VERSION 5.7 ;
  NOWIREEXTENSIONATPIN ON ;
  DIVIDERCHAR "/" ;
  BUSBITCHARS "[]" ;
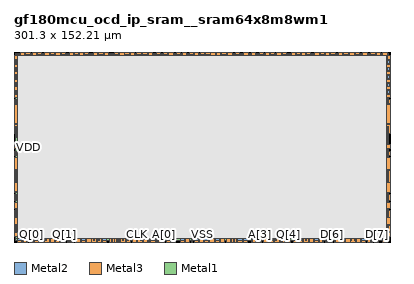
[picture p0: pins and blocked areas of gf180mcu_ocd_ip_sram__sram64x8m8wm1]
MACRO gf180mcu_ocd_ip_sram__sram64x8m8wm1
  CLASS BLOCK ;
  FOREIGN gf180mcu_ocd_ip_sram__sram64x8m8wm1 ;
  ORIGIN 0.000 0.000 ;
  SIZE 301.300 BY 152.210 ;
  PIN A[5]
    DIRECTION INPUT ;
    USE SIGNAL ;
    ANTENNADIFFAREA 0.928400 ;
    PORT
      LAYER Metal2 ;
        RECT 190.455 0.000 191.240 3.000 ;
    END
  END A[5]
  PIN A[4]
    DIRECTION INPUT ;
    USE SIGNAL ;
    ANTENNADIFFAREA 0.928400 ;
    PORT
      LAYER Metal2 ;
        RECT 193.070 0.000 193.855 3.000 ;
    END
  END A[4]
  PIN A[3]
    DIRECTION INPUT ;
    USE SIGNAL ;
    ANTENNADIFFAREA 0.928400 ;
    PORT
      LAYER Metal2 ;
        RECT 196.925 0.000 197.710 3.000 ;
    END
  END A[3]
  PIN A[2]
    DIRECTION INPUT ;
    USE SIGNAL ;
    ANTENNADIFFAREA 0.928400 ;
    PORT
      LAYER Metal2 ;
        RECT 108.005 0.000 108.790 3.000 ;
    END
  END A[2]
  PIN A[1]
    DIRECTION INPUT ;
    USE SIGNAL ;
    ANTENNADIFFAREA 0.928400 ;
    PORT
      LAYER Metal2 ;
        RECT 113.930 0.000 114.715 3.000 ;
    END
  END A[1]
  PIN A[0]
    DIRECTION INPUT ;
    USE SIGNAL ;
    ANTENNADIFFAREA 0.928400 ;
    PORT
      LAYER Metal2 ;
        RECT 119.850 0.000 120.630 3.000 ;
    END
  END A[0]
  PIN CEN
    DIRECTION INPUT ;
    USE SIGNAL ;
    ANTENNADIFFAREA 1.418650 ;
    PORT
      LAYER Metal2 ;
        RECT 176.195 0.000 176.980 3.000 ;
    END
  END CEN
  PIN CLK
    DIRECTION INPUT ;
    USE SIGNAL ;
    ANTENNAGATEAREA 9.738400 ;
    ANTENNADIFFAREA 0.490250 ;
    PORT
      LAYER Metal2 ;
        RECT 97.775 0.000 98.560 3.000 ;
    END
  END CLK
  PIN D[7]
    DIRECTION INPUT ;
    USE SIGNAL ;
    ANTENNAGATEAREA 0.249200 ;
    ANTENNADIFFAREA 0.490250 ;
    PORT
      LAYER Metal2 ;
        RECT 290.800 0.000 291.585 3.000 ;
    END
  END D[7]
  PIN D[6]
    DIRECTION INPUT ;
    USE SIGNAL ;
    ANTENNAGATEAREA 0.249200 ;
    ANTENNADIFFAREA 0.490250 ;
    PORT
      LAYER Metal2 ;
        RECT 254.605 0.000 255.385 3.000 ;
    END
  END D[6]
  PIN D[5]
    DIRECTION INPUT ;
    USE SIGNAL ;
    ANTENNAGATEAREA 0.249200 ;
    ANTENNADIFFAREA 0.490250 ;
    PORT
      LAYER Metal2 ;
        RECT 249.235 0.000 250.020 3.000 ;
    END
  END D[5]
  PIN D[4]
    DIRECTION INPUT ;
    USE SIGNAL ;
    ANTENNAGATEAREA 0.249200 ;
    ANTENNADIFFAREA 0.490250 ;
    PORT
      LAYER Metal2 ;
        RECT 214.060 0.000 214.845 3.000 ;
    END
  END D[4]
  PIN D[3]
    DIRECTION INPUT ;
    USE SIGNAL ;
    ANTENNAGATEAREA 0.249200 ;
    ANTENNADIFFAREA 0.490250 ;
    PORT
      LAYER Metal2 ;
        RECT 83.280 0.000 84.065 3.000 ;
    END
  END D[3]
  PIN D[2]
    DIRECTION INPUT ;
    USE SIGNAL ;
    ANTENNAGATEAREA 0.249200 ;
    ANTENNADIFFAREA 0.490250 ;
    PORT
      LAYER Metal2 ;
        RECT 47.085 0.000 47.870 3.000 ;
    END
  END D[2]
  PIN D[1]
    DIRECTION INPUT ;
    USE SIGNAL ;
    ANTENNAGATEAREA 0.249200 ;
    ANTENNADIFFAREA 0.490250 ;
    PORT
      LAYER Metal2 ;
        RECT 42.720 0.000 43.505 3.000 ;
    END
  END D[1]
  PIN D[0]
    DIRECTION INPUT ;
    USE SIGNAL ;
    ANTENNAGATEAREA 0.249200 ;
    ANTENNADIFFAREA 0.490250 ;
    PORT
      LAYER Metal2 ;
        RECT 6.520 0.000 7.305 3.000 ;
    END
  END D[0]
  PIN GWEN
    DIRECTION INPUT ;
    USE SIGNAL ;
    ANTENNAGATEAREA 3.141600 ;
    ANTENNADIFFAREA 0.490250 ;
    PORT
      LAYER Metal2 ;
        RECT 142.055 0.000 142.840 3.000 ;
    END
  END GWEN
  PIN Q[7]
    DIRECTION OUTPUT ;
    USE SIGNAL ;
    ANTENNADIFFAREA 5.315450 ;
    PORT
      LAYER Metal2 ;
        RECT 285.490 0.000 286.275 3.000 ;
    END
  END Q[7]
  PIN Q[6]
    DIRECTION OUTPUT ;
    USE SIGNAL ;
    ANTENNADIFFAREA 5.315450 ;
    PORT
      LAYER Metal2 ;
        RECT 256.960 0.000 257.740 3.000 ;
    END
  END Q[6]
  PIN Q[5]
    DIRECTION OUTPUT ;
    USE SIGNAL ;
    ANTENNADIFFAREA 5.315450 ;
    PORT
      LAYER Metal2 ;
        RECT 246.880 0.000 247.665 3.000 ;
    END
  END Q[5]
  PIN Q[4]
    DIRECTION OUTPUT ;
    USE SIGNAL ;
    ANTENNADIFFAREA 5.315450 ;
    PORT
      LAYER Metal2 ;
        RECT 219.350 0.000 220.135 3.000 ;
    END
  END Q[4]
  PIN Q[3]
    DIRECTION OUTPUT ;
    USE SIGNAL ;
    ANTENNADIFFAREA 5.315450 ;
    PORT
      LAYER Metal2 ;
        RECT 77.975 0.000 78.760 3.000 ;
    END
  END Q[3]
  PIN Q[2]
    DIRECTION OUTPUT ;
    USE SIGNAL ;
    ANTENNADIFFAREA 5.315450 ;
    PORT
      LAYER Metal2 ;
        RECT 49.440 0.000 50.225 3.000 ;
    END
  END Q[2]
  PIN Q[1]
    DIRECTION OUTPUT ;
    USE SIGNAL ;
    ANTENNADIFFAREA 5.315450 ;
    PORT
      LAYER Metal2 ;
        RECT 40.365 0.000 41.145 3.000 ;
    END
  END Q[1]
  PIN Q[0]
    DIRECTION OUTPUT ;
    USE SIGNAL ;
    ANTENNADIFFAREA 5.315450 ;
    PORT
      LAYER Metal2 ;
        RECT 13.830 0.000 14.610 3.000 ;
    END
  END Q[0]
  PIN VDD
    DIRECTION INOUT ;
    USE POWER ;
    PORT
      LAYER Metal2 ;
        RECT 2.470 149.260 298.830 149.410 ;
        RECT 2.465 149.210 298.830 149.260 ;
        RECT 2.465 3.000 3.000 149.210 ;
        RECT 298.300 145.630 298.830 149.210 ;
        RECT 298.300 4.330 298.835 145.630 ;
        RECT 298.300 3.000 298.830 4.330 ;
        RECT 2.465 1.410 5.970 3.000 ;
        RECT 2.470 0.985 5.970 1.410 ;
        RECT 295.330 0.985 298.830 3.000 ;
      LAYER Metal3 ;
        RECT 5.090 149.410 8.585 152.210 ;
        RECT 14.480 149.410 17.975 152.210 ;
        RECT 24.630 149.410 28.125 152.210 ;
        RECT 33.380 149.410 36.875 152.210 ;
        RECT 44.170 149.410 47.665 152.210 ;
        RECT 52.280 149.410 55.775 152.210 ;
        RECT 63.710 149.410 67.205 152.210 ;
        RECT 72.285 149.410 75.780 152.210 ;
        RECT 84.685 149.410 88.180 152.210 ;
        RECT 93.000 149.410 96.495 152.210 ;
        RECT 107.485 149.410 110.980 152.210 ;
        RECT 123.950 149.410 127.445 152.210 ;
        RECT 135.045 149.410 138.540 152.210 ;
        RECT 144.305 149.410 147.800 152.210 ;
        RECT 157.740 149.410 161.235 152.210 ;
        RECT 162.095 149.410 165.590 152.210 ;
        RECT 171.155 149.410 174.650 152.210 ;
        RECT 183.990 149.410 187.485 152.210 ;
        RECT 189.915 149.410 193.410 152.210 ;
        RECT 201.415 149.410 204.910 152.210 ;
        RECT 210.520 149.410 214.015 152.210 ;
        RECT 221.995 149.410 225.490 152.210 ;
        RECT 230.060 149.410 233.555 152.210 ;
        RECT 240.895 149.410 244.390 152.210 ;
        RECT 249.600 149.410 253.095 152.210 ;
        RECT 259.795 149.410 263.290 152.210 ;
        RECT 269.140 149.410 272.635 152.210 ;
        RECT 279.300 149.410 282.795 152.210 ;
        RECT 290.115 149.410 293.610 152.210 ;
        RECT 295.330 149.410 298.825 152.210 ;
        RECT 0.000 149.210 301.300 149.410 ;
        RECT 0.000 145.910 3.000 149.210 ;
        RECT 298.300 145.910 301.300 149.210 ;
        RECT 0.000 139.930 3.000 142.380 ;
        RECT 298.300 140.015 301.300 142.465 ;
        RECT 0.000 133.870 3.000 136.320 ;
        RECT 298.300 133.955 301.300 136.405 ;
        RECT 0.000 127.810 3.000 130.260 ;
        RECT 298.300 127.895 301.300 130.345 ;
        RECT 0.000 121.750 3.000 124.200 ;
        RECT 298.300 121.835 301.300 124.285 ;
        RECT 0.000 115.690 3.000 118.140 ;
        RECT 298.300 115.775 301.300 118.225 ;
        RECT 0.000 95.175 3.000 109.910 ;
        RECT 298.300 95.175 301.300 109.910 ;
        RECT 300.600 95.170 301.300 95.175 ;
        RECT 0.000 74.855 3.000 78.355 ;
        RECT 0.010 74.850 3.000 74.855 ;
        RECT 298.300 74.850 301.300 78.355 ;
        RECT 0.010 67.735 3.000 67.740 ;
        RECT 0.000 58.210 3.000 67.735 ;
        RECT 298.300 58.210 301.300 67.750 ;
        RECT 0.000 58.205 0.700 58.210 ;
        RECT 300.600 58.205 301.300 58.210 ;
        RECT 0.000 40.125 3.000 47.325 ;
        RECT 300.600 47.315 301.300 47.320 ;
        RECT 0.010 40.020 3.000 40.125 ;
        RECT 298.300 40.010 301.300 47.315 ;
        RECT 0.000 26.530 3.000 31.300 ;
        RECT 300.600 31.295 301.300 31.300 ;
        RECT 0.010 26.525 3.000 26.530 ;
        RECT 298.300 26.525 301.300 31.295 ;
        RECT 0.000 14.210 3.000 19.350 ;
        RECT 0.010 14.205 3.000 14.210 ;
        RECT 298.300 14.205 301.300 19.350 ;
        RECT 0.000 4.310 3.000 7.810 ;
        RECT 0.000 4.290 0.700 4.310 ;
        RECT 2.465 3.000 3.000 4.310 ;
        RECT 298.300 4.310 301.300 7.810 ;
        RECT 298.300 3.000 298.830 4.310 ;
        RECT 2.465 0.000 5.970 3.000 ;
        RECT 7.135 0.000 10.635 3.000 ;
        RECT 12.045 0.000 15.545 3.000 ;
        RECT 20.445 0.000 23.945 3.000 ;
        RECT 24.645 0.000 28.145 3.000 ;
        RECT 28.845 0.000 32.345 3.000 ;
        RECT 37.245 0.000 40.745 3.000 ;
        RECT 43.550 0.000 47.050 3.000 ;
        RECT 49.845 0.000 53.345 3.000 ;
        RECT 58.245 0.000 61.745 3.000 ;
        RECT 62.445 0.000 65.945 3.000 ;
        RECT 66.645 0.000 70.145 3.000 ;
        RECT 76.685 0.000 80.185 3.000 ;
        RECT 80.885 0.000 84.385 3.000 ;
        RECT 85.435 0.000 88.935 3.000 ;
        RECT 89.985 0.000 93.485 3.000 ;
        RECT 94.535 0.000 98.035 3.000 ;
        RECT 99.085 0.000 102.585 3.000 ;
        RECT 103.635 0.000 107.135 3.000 ;
        RECT 126.105 0.000 129.605 3.000 ;
        RECT 137.295 0.000 140.795 3.000 ;
        RECT 148.515 0.000 152.015 3.000 ;
        RECT 156.915 0.000 160.415 3.000 ;
        RECT 165.315 0.000 168.815 3.000 ;
        RECT 169.980 0.000 173.480 3.000 ;
        RECT 174.565 0.000 178.065 3.000 ;
        RECT 190.600 0.000 194.100 3.000 ;
        RECT 195.150 0.000 198.650 3.000 ;
        RECT 199.700 0.000 203.200 3.000 ;
        RECT 204.250 0.000 207.750 3.000 ;
        RECT 208.800 0.000 212.300 3.000 ;
        RECT 213.350 0.000 216.850 3.000 ;
        RECT 218.030 0.000 221.530 3.000 ;
        RECT 227.960 0.000 231.460 3.000 ;
        RECT 232.160 0.000 235.660 3.000 ;
        RECT 236.360 0.000 239.860 3.000 ;
        RECT 244.760 0.000 248.260 3.000 ;
        RECT 251.055 0.000 254.555 3.000 ;
        RECT 257.360 0.000 260.860 3.000 ;
        RECT 265.760 0.000 269.260 3.000 ;
        RECT 269.960 0.000 273.460 3.000 ;
        RECT 274.160 0.000 277.660 3.000 ;
        RECT 283.560 0.000 287.060 3.000 ;
        RECT 288.465 0.000 291.965 3.000 ;
        RECT 295.330 0.000 298.830 3.000 ;
    END
  END VDD
  PIN VSS
    DIRECTION INOUT ;
    USE GROUND ;
    PORT
      LAYER Metal1 ;
        RECT 0.985 149.210 300.315 151.220 ;
        RECT 0.985 3.000 3.000 149.210 ;
        RECT 298.300 3.000 300.315 149.210 ;
        RECT 0.985 0.985 300.315 3.000 ;
        RECT 87.030 0.980 87.730 0.985 ;
        RECT 90.590 0.980 91.290 0.985 ;
      LAYER Metal2 ;
        RECT 0.985 150.080 300.315 151.220 ;
        RECT 0.995 143.090 2.125 145.520 ;
        RECT 299.120 143.075 300.800 145.505 ;
        RECT 0.995 137.030 2.125 139.460 ;
        RECT 299.120 137.015 300.800 139.445 ;
        RECT 0.995 130.970 2.125 133.400 ;
        RECT 299.120 130.955 300.800 133.385 ;
        RECT 0.995 124.910 2.125 127.340 ;
        RECT 299.120 124.895 300.800 127.325 ;
        RECT 0.995 118.850 2.125 121.280 ;
        RECT 299.120 118.835 300.800 121.265 ;
        RECT 0.995 111.495 2.125 113.925 ;
        RECT 299.185 111.495 300.315 113.925 ;
        RECT 0.995 83.455 2.125 92.695 ;
        RECT 299.185 83.455 300.315 92.695 ;
        RECT 0.995 69.460 2.125 72.760 ;
        RECT 299.185 69.460 300.315 72.760 ;
        RECT 0.995 48.095 2.125 57.145 ;
        RECT 299.185 48.095 300.315 57.145 ;
        RECT 0.995 33.790 2.125 37.960 ;
        RECT 299.185 33.790 300.315 37.960 ;
        RECT 0.995 19.880 2.125 26.220 ;
        RECT 299.185 19.880 300.315 26.220 ;
        RECT 0.995 8.890 2.125 13.060 ;
        RECT 299.185 8.890 300.315 13.060 ;
        RECT 16.245 0.985 19.745 3.000 ;
        RECT 25.040 0.985 25.820 3.000 ;
        RECT 28.600 0.985 29.385 3.000 ;
        RECT 33.045 0.985 36.545 3.000 ;
        RECT 54.045 0.985 57.545 3.000 ;
        RECT 63.850 0.985 64.630 3.000 ;
        RECT 67.410 0.985 68.195 3.000 ;
        RECT 70.845 0.985 74.345 3.000 ;
        RECT 87.000 0.975 87.775 3.000 ;
        RECT 90.555 0.975 91.335 3.000 ;
        RECT 101.520 1.450 102.305 3.000 ;
        RECT 104.020 1.675 104.475 3.000 ;
        RECT 109.630 0.985 113.130 3.000 ;
        RECT 115.575 0.985 119.075 3.000 ;
        RECT 121.905 0.985 125.405 3.000 ;
        RECT 133.095 0.985 136.595 3.000 ;
        RECT 144.315 0.985 147.815 3.000 ;
        RECT 152.715 0.985 156.215 3.000 ;
        RECT 161.115 0.985 164.615 3.000 ;
        RECT 179.315 0.985 182.815 3.000 ;
        RECT 183.670 0.985 187.170 3.000 ;
        RECT 188.475 1.400 188.930 3.000 ;
        RECT 206.100 1.005 206.875 3.000 ;
        RECT 209.655 1.005 210.435 3.000 ;
        RECT 223.760 0.985 227.260 3.000 ;
        RECT 230.315 0.985 231.095 3.000 ;
        RECT 233.875 0.985 234.660 3.000 ;
        RECT 240.560 0.985 244.060 3.000 ;
        RECT 261.560 0.985 265.060 3.000 ;
        RECT 269.465 0.965 270.245 3.000 ;
        RECT 273.025 0.965 273.810 3.000 ;
        RECT 278.360 0.985 281.860 3.000 ;
      LAYER Metal3 ;
        RECT 9.370 150.075 12.870 152.210 ;
        RECT 18.760 150.080 22.260 152.210 ;
        RECT 28.910 150.075 32.410 152.210 ;
        RECT 37.660 150.080 41.160 152.210 ;
        RECT 48.450 150.075 51.950 152.210 ;
        RECT 56.560 150.080 60.060 152.210 ;
        RECT 67.990 150.075 71.490 152.210 ;
        RECT 80.400 150.075 83.900 152.210 ;
        RECT 88.805 150.080 92.305 152.210 ;
        RECT 98.320 150.080 101.820 152.210 ;
        RECT 103.205 150.080 106.705 152.210 ;
        RECT 114.085 150.080 117.585 152.210 ;
        RECT 119.835 150.080 123.335 152.210 ;
        RECT 130.070 150.080 133.570 152.210 ;
        RECT 140.340 150.080 143.840 152.210 ;
        RECT 149.255 150.080 152.755 152.210 ;
        RECT 153.745 150.080 157.245 152.210 ;
        RECT 166.375 150.080 169.875 152.210 ;
        RECT 177.380 150.080 180.880 152.210 ;
        RECT 196.715 150.080 200.215 152.210 ;
        RECT 205.520 150.080 209.020 152.210 ;
        RECT 214.800 150.075 218.300 152.210 ;
        RECT 226.275 150.080 229.775 152.210 ;
        RECT 234.340 150.075 237.840 152.210 ;
        RECT 245.175 150.080 248.675 152.210 ;
        RECT 253.880 150.075 257.380 152.210 ;
        RECT 264.075 150.080 267.575 152.210 ;
        RECT 273.420 150.075 276.920 152.210 ;
        RECT 285.830 150.075 289.330 152.210 ;
        RECT 0.000 143.080 3.000 145.530 ;
        RECT 298.300 143.065 301.300 145.515 ;
        RECT 0.000 137.020 3.000 139.470 ;
        RECT 298.300 137.005 301.300 139.455 ;
        RECT 0.000 130.960 3.000 133.410 ;
        RECT 298.300 130.945 301.300 133.395 ;
        RECT 0.000 124.900 3.000 127.350 ;
        RECT 298.300 124.885 301.300 127.335 ;
        RECT 0.000 118.840 3.000 121.290 ;
        RECT 298.300 118.825 301.300 121.275 ;
        RECT 0.010 114.115 3.000 114.360 ;
        RECT 0.000 111.350 3.000 114.115 ;
        RECT 0.010 111.345 3.000 111.350 ;
        RECT 298.300 111.345 301.300 114.360 ;
        RECT 0.000 86.895 3.000 93.830 ;
        RECT 0.010 86.890 3.000 86.895 ;
        RECT 298.300 86.890 301.300 93.830 ;
        RECT 0.000 72.855 0.700 72.860 ;
        RECT 0.000 69.355 3.000 72.855 ;
        RECT 298.300 69.355 301.300 72.860 ;
        RECT 0.000 47.950 3.000 57.210 ;
        RECT 298.300 47.950 301.300 57.210 ;
        RECT 0.000 33.615 3.000 38.225 ;
        RECT 298.300 33.615 301.300 38.230 ;
        RECT 0.000 19.810 3.000 25.465 ;
        RECT 298.300 19.810 301.300 25.465 ;
        RECT 0.000 13.195 0.700 13.200 ;
        RECT 0.000 8.740 3.000 13.195 ;
        RECT 298.300 8.750 301.300 13.195 ;
        RECT 16.245 0.000 19.745 3.000 ;
        RECT 33.045 0.000 36.545 3.000 ;
        RECT 54.045 0.000 57.545 3.000 ;
        RECT 70.845 0.000 74.345 3.000 ;
        RECT 109.630 0.000 113.130 3.000 ;
        RECT 115.575 0.000 119.075 3.000 ;
        RECT 121.905 0.000 125.405 3.000 ;
        RECT 133.095 0.000 136.595 3.000 ;
        RECT 144.315 0.000 147.815 3.000 ;
        RECT 152.715 0.000 156.215 3.000 ;
        RECT 161.115 0.000 164.615 3.000 ;
        RECT 179.315 0.000 182.815 3.000 ;
        RECT 183.670 0.000 187.170 3.000 ;
        RECT 223.760 0.000 227.260 3.000 ;
        RECT 240.560 0.000 244.060 3.000 ;
        RECT 261.560 0.000 265.060 3.000 ;
        RECT 278.360 0.000 281.860 3.000 ;
    END
  END VSS
  PIN WEN[7]
    DIRECTION INPUT ;
    USE SIGNAL ;
    ANTENNAGATEAREA 0.420000 ;
    ANTENNADIFFAREA 0.490250 ;
    PORT
      LAYER Metal2 ;
        RECT 288.430 0.000 289.215 3.000 ;
    END
  END WEN[7]
  PIN WEN[6]
    DIRECTION INPUT ;
    USE SIGNAL ;
    ANTENNAGATEAREA 0.420000 ;
    ANTENNADIFFAREA 0.490250 ;
    PORT
      LAYER Metal2 ;
        RECT 253.205 0.000 253.985 3.000 ;
    END
  END WEN[6]
  PIN WEN[5]
    DIRECTION INPUT ;
    USE SIGNAL ;
    ANTENNAGATEAREA 0.420000 ;
    ANTENNADIFFAREA 0.490250 ;
    PORT
      LAYER Metal2 ;
        RECT 250.630 0.000 251.410 3.000 ;
    END
  END WEN[5]
  PIN WEN[4]
    DIRECTION INPUT ;
    USE SIGNAL ;
    ANTENNAGATEAREA 0.420000 ;
    ANTENNADIFFAREA 0.490250 ;
    PORT
      LAYER Metal2 ;
        RECT 216.400 0.000 217.185 3.000 ;
    END
  END WEN[4]
  PIN WEN[3]
    DIRECTION INPUT ;
    USE SIGNAL ;
    ANTENNAGATEAREA 0.420000 ;
    ANTENNADIFFAREA 0.490250 ;
    PORT
      LAYER Metal2 ;
        RECT 81.910 0.000 82.695 3.000 ;
    END
  END WEN[3]
  PIN WEN[2]
    DIRECTION INPUT ;
    USE SIGNAL ;
    ANTENNAGATEAREA 0.420000 ;
    ANTENNADIFFAREA 0.490250 ;
    PORT
      LAYER Metal2 ;
        RECT 45.685 0.000 46.470 3.000 ;
    END
  END WEN[2]
  PIN WEN[1]
    DIRECTION INPUT ;
    USE SIGNAL ;
    ANTENNAGATEAREA 0.420000 ;
    ANTENNADIFFAREA 0.490250 ;
    PORT
      LAYER Metal2 ;
        RECT 44.110 0.000 44.895 3.000 ;
    END
  END WEN[1]
  PIN WEN[0]
    DIRECTION INPUT ;
    USE SIGNAL ;
    ANTENNAGATEAREA 0.420000 ;
    ANTENNADIFFAREA 0.490250 ;
    PORT
      LAYER Metal2 ;
        RECT 10.085 0.000 10.870 3.000 ;
    END
  END WEN[0]
  OBS
      LAYER Nwell ;
        RECT 6.305 5.770 295.010 147.090 ;
      LAYER Metal1 ;
        RECT 3.000 3.000 298.300 149.210 ;
      LAYER Metal2 ;
        RECT 3.000 3.000 298.300 149.210 ;
      LAYER Metal3 ;
        RECT 3.000 3.000 298.300 149.210 ;
  END
END gf180mcu_ocd_ip_sram__sram64x8m8wm1
END LIBRARY

